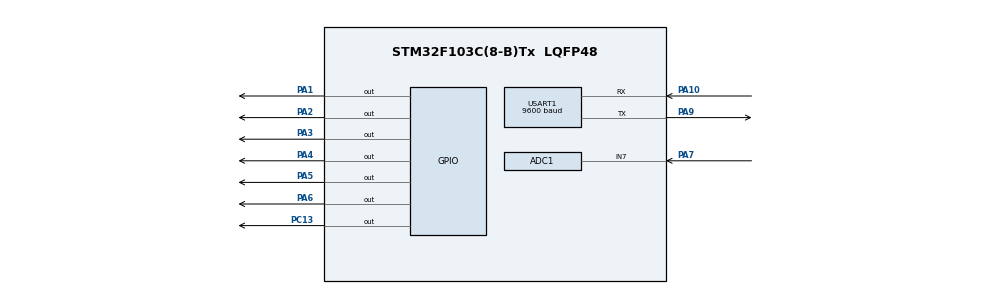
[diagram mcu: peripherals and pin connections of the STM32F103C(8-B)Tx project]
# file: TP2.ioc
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ADC1.Channel-0\#ChannelRegularConversion=ADC_CHANNEL_7
ADC1.NbrOfConversionFlag=1
ADC1.Rank-0\#ChannelRegularConversion=1
ADC1.SamplingTime-0\#ChannelRegularConversion=ADC_SAMPLETIME_1CYCLE_5
ADC1.master=1
Dma.ADC1.0.Direction=DMA_PERIPH_TO_MEMORY
Dma.ADC1.0.Instance=DMA1_Channel1
Dma.ADC1.0.MemDataAlignment=DMA_MDATAALIGN_HALFWORD
Dma.ADC1.0.MemInc=DMA_MINC_ENABLE
Dma.ADC1.0.Mode=DMA_NORMAL
Dma.ADC1.0.PeriphDataAlignment=DMA_PDATAALIGN_HALFWORD
Dma.ADC1.0.PeriphInc=DMA_PINC_DISABLE
Dma.ADC1.0.Priority=DMA_PRIORITY_LOW
Dma.Request0=ADC1
Mcu.Family=STM32F1
Mcu.Name=STM32F103C(8-B)Tx
Mcu.Package=LQFP48
NVIC.ADC1_2_IRQn=true\:0\:0\:false\:false\:true\:true\:true\:true
NVIC.DMA1_Channel1_IRQn=true\:0\:0\:false\:false\:true\:false\:true\:true
NVIC.PriorityGroup=NVIC_PRIORITYGROUP_4
NVIC.TIM2_IRQn=true\:0\:0\:false\:false\:true\:true\:true\:true
PA1.Signal=GPIO_Output
PA10.Mode=Asynchronous
PA10.Signal=USART1_RX
PA13.Mode=Serial_Wire
PA13.Signal=SYS_JTMS-SWDIO
PA14.Mode=Serial_Wire
PA14.Signal=SYS_JTCK-SWCLK
PA2.Signal=GPIO_Output
PA3.Signal=GPIO_Output
PA4.Signal=GPIO_Output
PA5.Signal=GPIO_Output
PA6.Signal=GPIO_Output
PA7.Signal=ADCx_IN7
PA9.Mode=Asynchronous
PA9.Signal=USART1_TX
PC13-TAMPER-RTC.Signal=GPIO_Output
PD0-OSC_IN.Mode=HSE-External-Oscillator
PD0-OSC_IN.Signal=RCC_OSC_IN
PD1-OSC_OUT.Mode=HSE-External-Oscillator
PD1-OSC_OUT.Signal=RCC_OSC_OUT
ProjectManager.HeapSize=0x200
ProjectManager.StackSize=0x400
ProjectManager.TargetToolchain=Makefile
RCC.ADCPresc=RCC_ADCPCLK2_DIV6
RCC.AHBFreq_Value=72000000
RCC.APB1CLKDivider=RCC_HCLK_DIV2
RCC.APB1Freq_Value=36000000
RCC.APB1TimFreq_Value=72000000
RCC.APB2Freq_Value=72000000
RCC.APB2TimFreq_Value=72000000
RCC.HCLKFreq_Value=72000000
RCC.PLLMUL=RCC_PLL_MUL9
RCC.PLLSourceVirtual=RCC_PLLSOURCE_HSE
RCC.SYSCLKFreq_VALUE=72000000
RCC.SYSCLKSource=RCC_SYSCLKSOURCE_PLLCLK
RCC.USBFreq_Value=72000000
SH.ADCx_IN7.0=ADC1_IN7,IN7
TIM2.AutoReloadPreload=TIM_AUTORELOAD_PRELOAD_ENABLE
TIM2.Period=7200
TIM2.Prescaler=1000
USART1.BaudRate=9600
USART1.VirtualMode=VM_ASYNC
VP_TIM2_VS_ClockSourceINT.Mode=Internal
board=custom

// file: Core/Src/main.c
/* USER CODE BEGIN Header */
/**
  ******************************************************************************
  * @file           : main.c
  * @brief          : Main program body
  ******************************************************************************
  * @attention
  *
  * Copyright (c) 2023 STMicroelectronics.
  * All rights reserved.
  *
  * This software is licensed under terms that can be found in the LICENSE file
  * in the root directory of this software component.
  * If no LICENSE file comes with this software, it is provided AS-IS.
  *
  ******************************************************************************
  */
/* USER CODE END Header */
#include "main.h"

ADC_HandleTypeDef hadc1;
DMA_HandleTypeDef hdma_adc1;

TIM_HandleTypeDef htim2;

UART_HandleTypeDef huart1;

PCD_HandleTypeDef hpcd_USB_FS;

void SystemClock_Config(void);
static void MX_GPIO_Init(void);
static void MX_DMA_Init(void);
static void MX_TIM2_Init(void);
static void MX_ADC1_Init(void);
static void MX_USB_PCD_Init(void);
static void MX_USART1_UART_Init(void);

int main(void)
{

  /* MCU Configuration--------------------------------------------------------*/

  /* Reset of all peripherals, Initializes the Flash interface and the Systick. */
  HAL_Init();

  /* Configure the system clock */
  SystemClock_Config();

  /* Initialize all configured peripherals */
  MX_GPIO_Init();
  MX_DMA_Init();
  MX_TIM2_Init();
  MX_ADC1_Init();
  MX_USB_PCD_Init();
  MX_USART1_UART_Init();

  /* Infinite loop */
  while (1)
  {

  }
}

void SystemClock_Config(void)
{
  RCC_OscInitTypeDef RCC_OscInitStruct = {0};
  RCC_ClkInitTypeDef RCC_ClkInitStruct = {0};
  RCC_PeriphCLKInitTypeDef PeriphClkInit = {0};

  /** Initializes the RCC Oscillators according to the specified parameters
  * in the RCC_OscInitTypeDef structure.
  */
  RCC_OscInitStruct.OscillatorType = RCC_OSCILLATORTYPE_HSE;
  RCC_OscInitStruct.HSEState = RCC_HSE_ON;
  RCC_OscInitStruct.HSEPredivValue = RCC_HSE_PREDIV_DIV1;
  RCC_OscInitStruct.HSIState = RCC_HSI_ON;
  RCC_OscInitStruct.PLL.PLLState = RCC_PLL_ON;
  RCC_OscInitStruct.PLL.PLLSource = RCC_PLLSOURCE_HSE;
  RCC_OscInitStruct.PLL.PLLMUL = RCC_PLL_MUL6;
  if (HAL_RCC_OscConfig(&RCC_OscInitStruct) != HAL_OK)
  {
    Error_Handler();
  }

  /** Initializes the CPU, AHB and APB buses clocks
  */
  RCC_ClkInitStruct.ClockType = RCC_CLOCKTYPE_HCLK|RCC_CLOCKTYPE_SYSCLK
                              |RCC_CLOCKTYPE_PCLK1|RCC_CLOCKTYPE_PCLK2;
  RCC_ClkInitStruct.SYSCLKSource = RCC_SYSCLKSOURCE_PLLCLK;
  RCC_ClkInitStruct.AHBCLKDivider = RCC_SYSCLK_DIV1;
  RCC_ClkInitStruct.APB1CLKDivider = RCC_HCLK_DIV2;
  RCC_ClkInitStruct.APB2CLKDivider = RCC_HCLK_DIV1;

  if (HAL_RCC_ClockConfig(&RCC_ClkInitStruct, FLASH_LATENCY_1) != HAL_OK)
  {
    Error_Handler();
  }
  PeriphClkInit.PeriphClockSelection = RCC_PERIPHCLK_ADC|RCC_PERIPHCLK_USB;
  PeriphClkInit.AdcClockSelection = RCC_ADCPCLK2_DIV4;
  PeriphClkInit.UsbClockSelection = RCC_USBCLKSOURCE_PLL;
  if (HAL_RCCEx_PeriphCLKConfig(&PeriphClkInit) != HAL_OK)
  {
    Error_Handler();
  }
}

static void MX_ADC1_Init(void)
{

  ADC_ChannelConfTypeDef sConfig = {0};

  /** Common config
  */
  hadc1.Instance = ADC1;
  hadc1.Init.ScanConvMode = ADC_SCAN_DISABLE;
  hadc1.Init.ContinuousConvMode = DISABLE;
  hadc1.Init.DiscontinuousConvMode = DISABLE;
  hadc1.Init.ExternalTrigConv = ADC_SOFTWARE_START;
  hadc1.Init.DataAlign = ADC_DATAALIGN_RIGHT;
  hadc1.Init.NbrOfConversion = 1;
  if (HAL_ADC_Init(&hadc1) != HAL_OK)
  {
    Error_Handler();
  }

  /** Configure Regular Channel
  */
  sConfig.Channel = ADC_CHANNEL_7;
  sConfig.Rank = ADC_REGULAR_RANK_1;
  sConfig.SamplingTime = ADC_SAMPLETIME_1CYCLE_5;
  if (HAL_ADC_ConfigChannel(&hadc1, &sConfig) != HAL_OK)
  {
    Error_Handler();
  }

}

static void MX_TIM2_Init(void)
{

  TIM_ClockConfigTypeDef sClockSourceConfig = {0};
  TIM_MasterConfigTypeDef sMasterConfig = {0};

  htim2.Instance = TIM2;
  htim2.Init.Prescaler = 1000;
  htim2.Init.CounterMode = TIM_COUNTERMODE_UP;
  htim2.Init.Period = 7200;
  htim2.Init.ClockDivision = TIM_CLOCKDIVISION_DIV1;
  htim2.Init.AutoReloadPreload = TIM_AUTORELOAD_PRELOAD_ENABLE;
  if (HAL_TIM_Base_Init(&htim2) != HAL_OK)
  {
    Error_Handler();
  }
  sClockSourceConfig.ClockSource = TIM_CLOCKSOURCE_INTERNAL;
  if (HAL_TIM_ConfigClockSource(&htim2, &sClockSourceConfig) != HAL_OK)
  {
    Error_Handler();
  }
  sMasterConfig.MasterOutputTrigger = TIM_TRGO_RESET;
  sMasterConfig.MasterSlaveMode = TIM_MASTERSLAVEMODE_DISABLE;
  if (HAL_TIMEx_MasterConfigSynchronization(&htim2, &sMasterConfig) != HAL_OK)
  {
    Error_Handler();
  }

}

static void MX_USART1_UART_Init(void)
{

  huart1.Instance = USART1;
  huart1.Init.BaudRate = 9600;
  huart1.Init.WordLength = UART_WORDLENGTH_8B;
  huart1.Init.StopBits = UART_STOPBITS_1;
  huart1.Init.Parity = UART_PARITY_NONE;
  huart1.Init.Mode = UART_MODE_TX_RX;
  huart1.Init.HwFlowCtl = UART_HWCONTROL_NONE;
  huart1.Init.OverSampling = UART_OVERSAMPLING_16;
  if (HAL_UART_Init(&huart1) != HAL_OK)
  {
    Error_Handler();
  }

}

static void MX_USB_PCD_Init(void)
{

  hpcd_USB_FS.Instance = USB;
  hpcd_USB_FS.Init.dev_endpoints = 8;
  hpcd_USB_FS.Init.speed = PCD_SPEED_FULL;
  hpcd_USB_FS.Init.low_power_enable = DISABLE;
  hpcd_USB_FS.Init.lpm_enable = DISABLE;
  hpcd_USB_FS.Init.battery_charging_enable = DISABLE;
  if (HAL_PCD_Init(&hpcd_USB_FS) != HAL_OK)
  {
    Error_Handler();
  }

}

static void MX_DMA_Init(void)
{

  /* DMA controller clock enable */
  __HAL_RCC_DMA1_CLK_ENABLE();

  /* DMA interrupt init */
  /* DMA1_Channel1_IRQn interrupt configuration */
  HAL_NVIC_SetPriority(DMA1_Channel1_IRQn, 0, 0);
  HAL_NVIC_EnableIRQ(DMA1_Channel1_IRQn);

}

static void MX_GPIO_Init(void)
{
  GPIO_InitTypeDef GPIO_InitStruct = {0};

  /* GPIO Ports Clock Enable */
  __HAL_RCC_GPIOC_CLK_ENABLE();
  __HAL_RCC_GPIOD_CLK_ENABLE();
  __HAL_RCC_GPIOA_CLK_ENABLE();

  /*Configure GPIO pin Output Level */
  HAL_GPIO_WritePin(GPIOC, GPIO_PIN_13, GPIO_PIN_RESET);

  /*Configure GPIO pin Output Level */
  HAL_GPIO_WritePin(GPIOA, GPIO_PIN_1|GPIO_PIN_2|GPIO_PIN_3|GPIO_PIN_4
                          |GPIO_PIN_5|GPIO_PIN_6, GPIO_PIN_RESET);

  /*Configure GPIO pin : PC13 */
  GPIO_InitStruct.Pin = GPIO_PIN_13;
  GPIO_InitStruct.Mode = GPIO_MODE_OUTPUT_PP;
  GPIO_InitStruct.Pull = GPIO_NOPULL;
  GPIO_InitStruct.Speed = GPIO_SPEED_FREQ_LOW;
  HAL_GPIO_Init(GPIOC, &GPIO_InitStruct);

  /*Configure GPIO pins : PA1 PA2 PA3 PA4
                           PA5 PA6 */
  GPIO_InitStruct.Pin = GPIO_PIN_1|GPIO_PIN_2|GPIO_PIN_3|GPIO_PIN_4
                          |GPIO_PIN_5|GPIO_PIN_6;
  GPIO_InitStruct.Mode = GPIO_MODE_OUTPUT_PP;
  GPIO_InitStruct.Pull = GPIO_NOPULL;
  GPIO_InitStruct.Speed = GPIO_SPEED_FREQ_LOW;
  HAL_GPIO_Init(GPIOA, &GPIO_InitStruct);

}

void Error_Handler(void)
{
  __disable_irq();
  while (1)
  {
  }
}
